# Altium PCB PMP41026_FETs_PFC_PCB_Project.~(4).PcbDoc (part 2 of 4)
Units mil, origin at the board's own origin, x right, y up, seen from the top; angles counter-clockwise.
Board outline 2440.95 x 1417.32 mil, 6 copper layers (Top Layer, Signal Layer 1, Signal Layer 2, Signal Layer 3, Signal Layer 4, Bottom Layer), stack 69.8 mil thick; 61 components, 66 nets, 254 pads, 775 vias.
Unrouted connection lines stored in the file: 2.

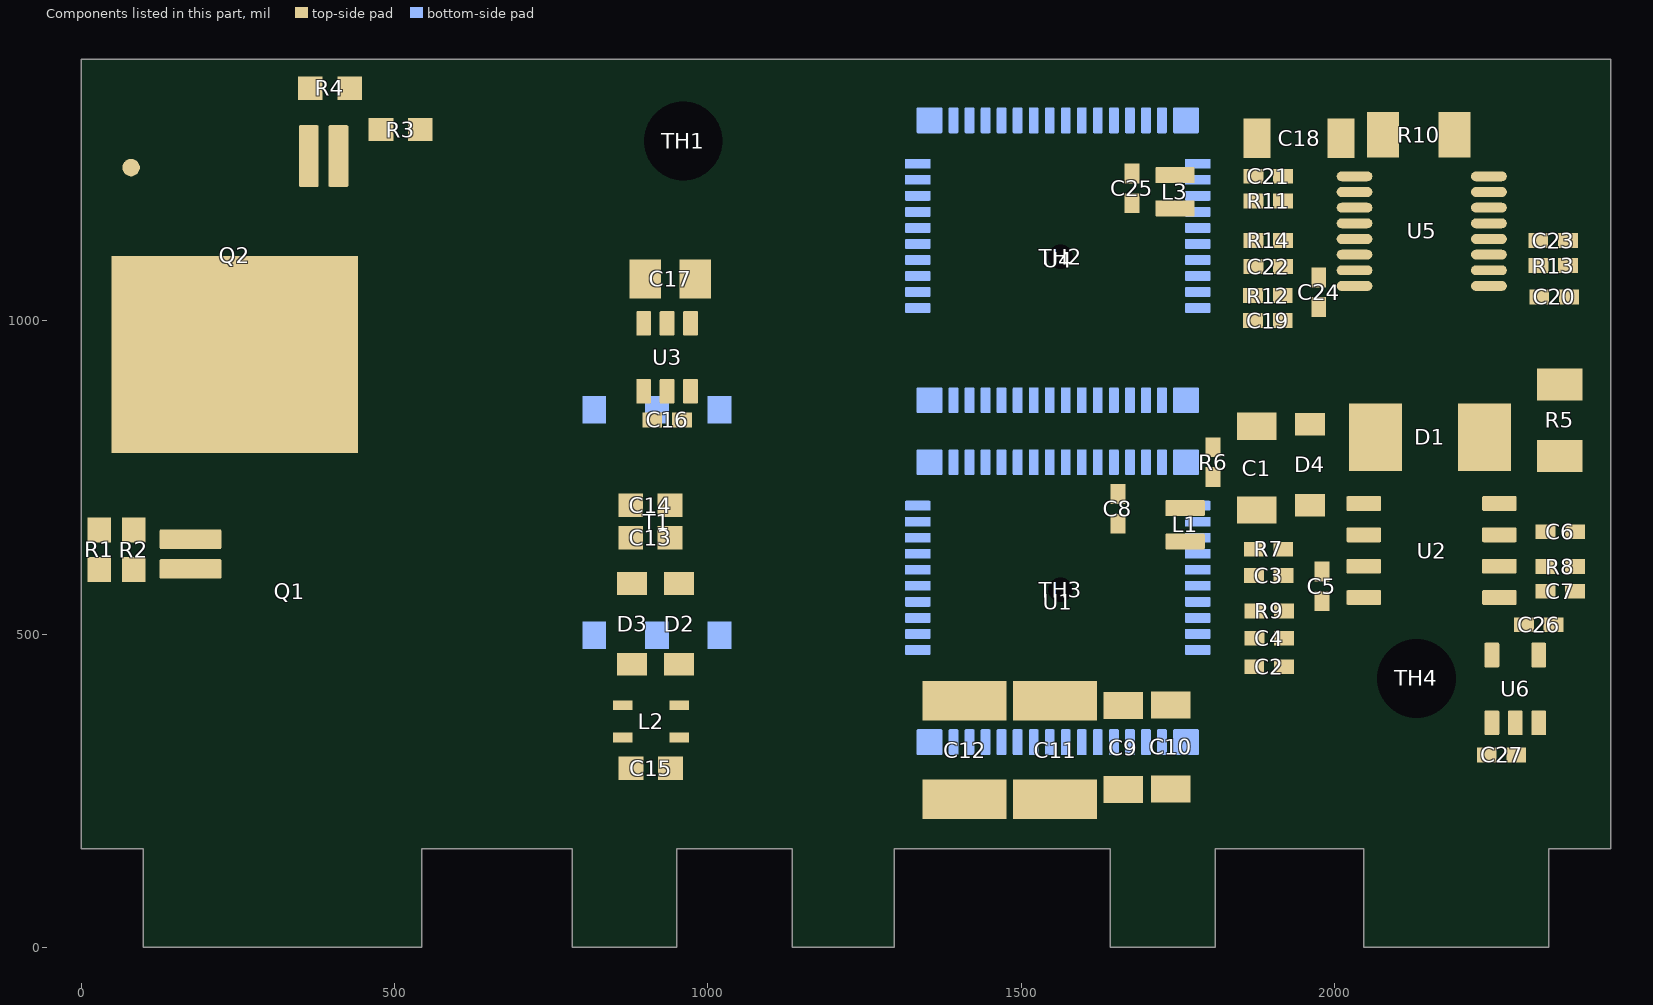
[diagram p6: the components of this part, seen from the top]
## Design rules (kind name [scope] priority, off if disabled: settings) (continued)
PolygonConnect PolygonConnect_38 [All vs IsNamedPolygon('SWNODE') Or  IsNamedPolygon('D403_2') Or  IsNamedPolygon('D403_2') Or  IsNamedPolygon('PGND') Or  IsNamedPolygon('BOTTOM_LAYER_NETC106_2_P030') Or  IsNamedPolygon('C102_1') Or  IsNamedPolygon('SGND') Or  IsNamedPolygon('TOP_LAYER_54V1_P046') Or  IsNamedPolygon('TOP_LAYER_54V2_P048') Or  IsNamedPolygon('TOP_LAYER_54V2_P048') Or  IsNamedPolygon('C108_1') Or  IsNamedPolygon('C108_1') Or  IsNamedPolygon('C108_1') Or  IsNamedPolygon('C108_1') Or  IsNamedPolygon('C108_1') Or  IsNamedPolygon('C108_1') Or  IsNamedPolygon('PGND') Or  IsNamedPolygon('ZCD') Or  IsNamedPolygon('Line') Or  IsNamedPolygon('5Vp') Or  IsNamedPolygon('12Vp') Or  IsNamedPolygon('T200_4') Or  IsNamedPolygon('T200_6') Or  IsNamedPolygon('SWNODE3') Or  IsNamedPolygon('T200_4') Or  IsNamedPolygon('T200_6') Or  IsNamedPolygon('SWNODE4') Or  IsNamedPolygon('VSR') Or  IsNamedPolygon('Iout_SNS') Or  IsNamedPolygon('SIGNAL_LAYER_2_VBB_P094') Or  IsNamedPolygon('Vbulk1') Or  IsNamedPolygon('VBB') Or  IsNamedPolygon('SIGNAL_LAYER_1_VBULK1_P106') Or  IsNamedPolygon('Line') Or  IsNamedPolygon('Line') Or  IsNamedPolygon('Line') Or  IsNamedPolygon('D404_2') Or  IsNamedPolygon('VBB') Or  IsNamedPolygon('D400_2') Or  IsNamedPolygon('SGND') Or  IsNamedPolygon('PGND') Or  IsNamedPolygon('TOP_LAYER_12VS_P126') Or  IsNamedPolygon('BOTTOM_LAYER_54V1_P128') Or  IsNamedPolygon('LEG3_HS_DRV') Or  IsNamedPolygon('LEG4_LS_DRV') Or  IsNamedPolygon('LEG4_HS_DRV') Or  IsNamedPolygon('SWNODE4') Or  IsNamedPolygon('SWNODE3') Or  IsNamedPolygon('T200_6') Or  IsNamedPolygon('T200_4') Or  IsNamedPolygon('VBB') Or  IsNamedPolygon('5Vs') Or  IsNamedPolygon('SGND') Or  IsNamedPolygon('Iout_SNS') Or  IsNamedPolygon('SGND') Or  IsNamedPolygon('SWNODE3') Or  IsNamedPolygon('SWNODE3') Or  IsNamedPolygon('SWNODE3') Or  IsNamedPolygon('SWNODE3') Or  IsNamedPolygon('SGND') Or  IsNamedPolygon('SGND') Or  IsNamedPolygon('SGND') Or  IsNamedPolygon('SWNODE4') Or  IsNamedPolygon('SWNODE4') Or  IsNamedPolygon('SWNODE4') Or  IsNamedPolygon('VSR') Or  IsNamedPolygon('SWNODE3') Or  IsNamedPolygon('SGND') Or  IsNamedPolygon('SGND') Or  IsNamedPolygon('SGND') Or  IsNamedPolygon('SGND') Or  IsNamedPolygon('SGND') Or  IsNamedPolygon('SGND') Or  IsNamedPolygon('BOTTOM_LAYER_54V1_P128') Or  IsNamedPolygon('SGND') Or  IsNamedPolygon('VSR') Or  IsNamedPolygon('C102_1') Or  IsNamedPolygon('C102_1') Or  IsNamedPolygon('C102_1') Or  IsNamedPolygon('C102_1') Or  IsNamedPolygon('C102_1') Or  IsNamedPolygon('ZCD') Or  IsNamedPolygon('PGND') Or  IsNamedPolygon('PGND') Or  IsNamedPolygon('Vbulk1') Or  IsNamedPolygon('VBB') Or  IsNamedPolygon('Vbulk1') Or  IsNamedPolygon('Vbulk1') Or  IsNamedPolygon('ZCD') Or  IsNamedPolygon('Neutral') Or  IsNamedPolygon('Neutral')] p22: connectstyle=Direct reliefconductorwidth=10 reliefentries=4 polygonreliefangle="90 Angle" airgapwidth=10
PolygonConnect PolygonConnect_37 [All vs IsNamedPolygon('SGND') Or  IsNamedPolygon('SWNODE4') Or  IsNamedPolygon('5Vp') Or  IsNamedPolygon('SWNODE4') Or  IsNamedPolygon('VBB') Or  IsNamedPolygon('Line') Or  IsNamedPolygon('SGND') Or  IsNamedPolygon('SIGNAL_LAYER_2_C102_1_P032') Or  IsNamedPolygon('TOP_LAYER_54V2_P048') Or  IsNamedPolygon('ZCD') Or  IsNamedPolygon('PGND') Or  IsNamedPolygon('SIGNAL_LAYER_2_VBB_P094') Or  IsNamedPolygon('Line') Or  IsNamedPolygon('Line') Or  IsNamedPolygon('D404_2') Or  IsNamedPolygon('PGND') Or  IsNamedPolygon('SIGNAL_LAYER_1_ZCD_P108') Or  IsNamedPolygon('SWNODE3') Or  IsNamedPolygon('SIGNAL_LAYER_4_C102_1_P038') Or  IsNamedPolygon('SWNODE3') Or  IsNamedPolygon('LEG4_HS_DRV') Or  IsNamedPolygon('SWNODE4') Or  IsNamedPolygon('5Vs') Or  IsNamedPolygon('VBB') Or  IsNamedPolygon('TOP_LAYER_54V2_P048') Or  IsNamedPolygon('C102_1') Or  IsNamedPolygon('LEG4_LS_DRV') Or  IsNamedPolygon('T200_4') Or  IsNamedPolygon('SWNODE3') Or  IsNamedPolygon('Line') Or  IsNamedPolygon('SGND') Or  IsNamedPolygon('SGND') Or  IsNamedPolygon('SWNODE4') Or  IsNamedPolygon('12Vp') Or  IsNamedPolygon('BOTTOM_LAYER_NETC106_2_P030') Or  IsNamedPolygon('T200_4') Or  IsNamedPolygon('Vbulk1') Or  IsNamedPolygon('C108_1') Or  IsNamedPolygon('BOTTOM_LAYER_54V1_P128') Or  IsNamedPolygon('BOTTOM_LAYER_54V1_P128') Or  IsNamedPolygon('SWNODE') Or  IsNamedPolygon('Iout_SNS') Or  IsNamedPolygon('VSR') Or  IsNamedPolygon('D400_2') Or  IsNamedPolygon('D403_2') Or  IsNamedPolygon('SWNODE3') Or  IsNamedPolygon('T200_6') Or  IsNamedPolygon('SWNODE3') Or  IsNamedPolygon('C108_1') Or  IsNamedPolygon('PGND') Or  IsNamedPolygon('BOTTOM_LAYER_VBULK1_P096') Or  IsNamedPolygon('BOTTOM_LAYER_54V1_P128') Or  IsNamedPolygon('TOP_LAYER_12VS_P126') Or  IsNamedPolygon('SIGNAL_LAYER_1_VBULK1_P106') Or  IsNamedPolygon('T200_4') Or  IsNamedPolygon('SGND') Or  IsNamedPolygon('C108_1') Or  IsNamedPolygon('SWNODE3') Or  IsNamedPolygon('T200_6') Or  IsNamedPolygon('T200_6') Or  IsNamedPolygon('T200_6') Or  IsNamedPolygon('SGND') Or  IsNamedPolygon('C108_1') Or  IsNamedPolygon('SGND') Or  IsNamedPolygon('VBB') Or  IsNamedPolygon('T200_4') Or  IsNamedPolygon('LEG3_HS_DRV') Or  IsNamedPolygon('C108_1') Or  IsNamedPolygon('D403_2') Or  IsNamedPolygon('Iout_SNS') Or  IsNamedPolygon('C108_1') Or  IsNamedPolygon('SWNODE4')] p23: connectstyle=Direct reliefconductorwidth=10 reliefentries=4 polygonreliefangle="90 Angle" airgapwidth=10
PolygonConnect PolygonConnect_36 [All vs IsNamedPolygon('PGND') Or  IsNamedPolygon('BOTTOM_LAYER_54V1_P128') Or  IsNamedPolygon('SGND') Or  IsNamedPolygon('LEG4_LS_DRV') Or  IsNamedPolygon('TOP_LAYER_12VS_P126') Or  IsNamedPolygon('LEG4_HS_DRV') Or  IsNamedPolygon('LEG3_HS_DRV') Or  IsNamedPolygon('SGND') Or  IsNamedPolygon('C108_1') Or  IsNamedPolygon('12Vp') Or  IsNamedPolygon('D403_2') Or  IsNamedPolygon('SIGNAL_LAYER_1_ZCD_P108') Or  IsNamedPolygon('C108_1') Or  IsNamedPolygon('BOTTOM_LAYER_VBULK1_P096') Or  IsNamedPolygon('SWNODE') Or  IsNamedPolygon('T200_4') Or  IsNamedPolygon('D400_2') Or  IsNamedPolygon('C102_1') Or  IsNamedPolygon('Line') Or  IsNamedPolygon('VBB') Or  IsNamedPolygon('Line') Or  IsNamedPolygon('TOP_LAYER_54V2_P048') Or  IsNamedPolygon('BOTTOM_LAYER_NETC106_2_P030') Or  IsNamedPolygon('SIGNAL_LAYER_1_VBULK1_P106') Or  IsNamedPolygon('Line') Or  IsNamedPolygon('5Vp') Or  IsNamedPolygon('BOTTOM_LAYER_54V1_P128') Or  IsNamedPolygon('D404_2') Or  IsNamedPolygon('C108_1') Or  IsNamedPolygon('VSR') Or  IsNamedPolygon('T200_6') Or  IsNamedPolygon('VBB') Or  IsNamedPolygon('C108_1') Or  IsNamedPolygon('SIGNAL_LAYER_2_C102_1_P032') Or  IsNamedPolygon('SGND') Or  IsNamedPolygon('PGND') Or  IsNamedPolygon('SIGNAL_LAYER_4_C102_1_P038') Or  IsNamedPolygon('Vbulk1') Or  IsNamedPolygon('TOP_LAYER_54V2_P048') Or  IsNamedPolygon('Iout_SNS') Or  IsNamedPolygon('PGND') Or  IsNamedPolygon('T200_4') Or  IsNamedPolygon('ZCD') Or  IsNamedPolygon('Line') Or  IsNamedPolygon('C108_1') Or  IsNamedPolygon('D403_2') Or  IsNamedPolygon('SIGNAL_LAYER_2_VBB_P094') Or  IsNamedPolygon('SGND') Or  IsNamedPolygon('C108_1') Or  IsNamedPolygon('SIGNAL_LAYER_1_IOUT_SNS_P044') Or  IsNamedPolygon('BOTTOM_LAYER_54V1_P128') Or  IsNamedPolygon('T200_6')] p24: connectstyle=Direct reliefconductorwidth=10 reliefentries=4 polygonreliefangle="90 Angle" airgapwidth=10
PolygonConnect PolygonConnect_35 [All vs IsNamedPolygon('SWNODE') Or  IsNamedPolygon('D403_2') Or  IsNamedPolygon('D403_2') Or  IsNamedPolygon('PGND') Or  IsNamedPolygon('BOTTOM_LAYER_NETC106_2_P030') Or  IsNamedPolygon('SIGNAL_LAYER_2_C102_1_P032') Or  IsNamedPolygon('C102_1') Or  IsNamedPolygon('SIGNAL_LAYER_4_C102_1_P038') Or  IsNamedPolygon('SGND') Or  IsNamedPolygon('SIGNAL_LAYER_1_IOUT_SNS_P044') Or  IsNamedPolygon('BOTTOM_LAYER_54V1_P128') Or  IsNamedPolygon('TOP_LAYER_54V2_P048') Or  IsNamedPolygon('BOTTOM_LAYER_54V1_P128') Or  IsNamedPolygon('TOP_LAYER_54V2_P048') Or  IsNamedPolygon('C108_1') Or  IsNamedPolygon('C108_1') Or  IsNamedPolygon('C108_1') Or  IsNamedPolygon('C108_1') Or  IsNamedPolygon('C108_1') Or  IsNamedPolygon('C108_1') Or  IsNamedPolygon('PGND') Or  IsNamedPolygon('ZCD') Or  IsNamedPolygon('Line') Or  IsNamedPolygon('5Vp') Or  IsNamedPolygon('12Vp') Or  IsNamedPolygon('T200_4') Or  IsNamedPolygon('T200_6') Or  IsNamedPolygon('SGND') Or  IsNamedPolygon('T200_4') Or  IsNamedPolygon('T200_6') Or  IsNamedPolygon('SGND') Or  IsNamedPolygon('VSR') Or  IsNamedPolygon('Iout_SNS') Or  IsNamedPolygon('SIGNAL_LAYER_2_VBB_P094') Or  IsNamedPolygon('BOTTOM_LAYER_VBULK1_P096') Or  IsNamedPolygon('Vbulk1') Or  IsNamedPolygon('VBB') Or  IsNamedPolygon('SIGNAL_LAYER_1_VBULK1_P106') Or  IsNamedPolygon('SIGNAL_LAYER_1_ZCD_P108') Or  IsNamedPolygon('Line') Or  IsNamedPolygon('Line') Or  IsNamedPolygon('Line') Or  IsNamedPolygon('D404_2') Or  IsNamedPolygon('VBB') Or  IsNamedPolygon('D400_2') Or  IsNamedPolygon('SGND') Or  IsNamedPolygon('PGND') Or  IsNamedPolygon('TOP_LAYER_12VS_P126') Or  IsNamedPolygon('BOTTOM_LAYER_54V1_P128') Or  IsNamedPolygon('LEG3_HS_DRV')] p25: connectstyle=Direct reliefconductorwidth=10 reliefentries=4 polygonreliefangle="90 Angle" airgapwidth=10
PolygonConnect PolygonConnect_34 [All vs IsNamedPolygon('SWNODE') Or  IsNamedPolygon('D403_2') Or  IsNamedPolygon('D403_2') Or  IsNamedPolygon('PGND') Or  IsNamedPolygon('BOTTOM_LAYER_NETC106_2_P030') Or  IsNamedPolygon('SIGNAL_LAYER_2_C102_1_P032') Or  IsNamedPolygon('C102_1') Or  IsNamedPolygon('SIGNAL_LAYER_4_C102_1_P038') Or  IsNamedPolygon('SGND') Or  IsNamedPolygon('SIGNAL_LAYER_1_IOUT_SNS_P044') Or  IsNamedPolygon('BOTTOM_LAYER_54V1_P128') Or  IsNamedPolygon('TOP_LAYER_54V2_P048') Or  IsNamedPolygon('BOTTOM_LAYER_54V1_P128') Or  IsNamedPolygon('TOP_LAYER_54V2_P048') Or  IsNamedPolygon('C108_1') Or  IsNamedPolygon('C108_1') Or  IsNamedPolygon('C108_1') Or  IsNamedPolygon('C108_1') Or  IsNamedPolygon('C108_1') Or  IsNamedPolygon('C108_1') Or  IsNamedPolygon('PGND') Or  IsNamedPolygon('ZCD') Or  IsNamedPolygon('Line') Or  IsNamedPolygon('5Vp') Or  IsNamedPolygon('12Vp') Or  IsNamedPolygon('T200_4') Or  IsNamedPolygon('T200_6') Or  IsNamedPolygon('SGND') Or  IsNamedPolygon('T200_4') Or  IsNamedPolygon('T200_6') Or  IsNamedPolygon('SGND') Or  IsNamedPolygon('VSR') Or  IsNamedPolygon('Iout_SNS') Or  IsNamedPolygon('SIGNAL_LAYER_2_VBB_P094') Or  IsNamedPolygon('BOTTOM_LAYER_VBULK1_P096') Or  IsNamedPolygon('Vbulk1') Or  IsNamedPolygon('VBB') Or  IsNamedPolygon('SIGNAL_LAYER_1_VBULK1_P106') Or  IsNamedPolygon('SIGNAL_LAYER_1_ZCD_P108') Or  IsNamedPolygon('Line') Or  IsNamedPolygon('Line') Or  IsNamedPolygon('Line') Or  IsNamedPolygon('D404_2') Or  IsNamedPolygon('VBB') Or  IsNamedPolygon('D400_2') Or  IsNamedPolygon('SGND')] p26: connectstyle=Direct reliefconductorwidth=10 reliefentries=4 polygonreliefangle="90 Angle" airgapwidth=10
PolygonConnect PolygonConnect_33 [All vs IsNamedPolygon('SIGNAL_LAYER_1_VBULK1_P106')] p27: connectstyle=Direct reliefconductorwidth=10 reliefentries=4 polygonreliefangle="90 Angle" airgapwidth=10
PolygonConnect PolygonConnect_32 [All vs IsNamedPolygon('SIGNAL_LAYER_1_VBULK1_P106')] p28: connectstyle=Direct reliefconductorwidth=10 reliefentries=4 polygonreliefangle="90 Angle" airgapwidth=10
PolygonConnect PolygonConnect_31 [All vs IsNamedPolygon('SIGNAL_LAYER_1_VBULK1_P106')] p29: connectstyle=Direct reliefconductorwidth=10 reliefentries=4 polygonreliefangle="90 Angle" airgapwidth=10
PolygonConnect PolygonConnect_30 [All vs IsNamedPolygon('VBB')] p30: connectstyle=Direct reliefconductorwidth=10 reliefentries=4 polygonreliefangle="90 Angle" airgapwidth=10
PolygonConnect PolygonConnect_29 [All vs IsNamedPolygon('SGND')] p31: connectstyle=Direct reliefconductorwidth=10 reliefentries=4 polygonreliefangle="90 Angle" airgapwidth=10
PolygonConnect PolygonConnect_28 [All vs IsNamedPolygon('Vbulk1')] p32: connectstyle=Direct reliefconductorwidth=10 reliefentries=4 polygonreliefangle="90 Angle" airgapwidth=10
PolygonConnect PolygonConnect_27 [All vs IsNamedPolygon('BOTTOM_LAYER_VBULK1_P096')] p33: connectstyle=Direct reliefconductorwidth=10 reliefentries=4 polygonreliefangle="90 Angle" airgapwidth=10
PolygonConnect PolygonConnect_26 [All vs IsNamedPolygon('SIGNAL_LAYER_2_VBB_P094')] p34: connectstyle=Direct reliefconductorwidth=10 reliefentries=4 polygonreliefangle="90 Angle" airgapwidth=10
PolygonConnect PolygonConnect_25 [All vs IsNamedPolygon('C108_1')] p35: connectstyle=Direct reliefconductorwidth=10 reliefentries=4 polygonreliefangle="90 Angle" airgapwidth=10
PolygonConnect PolygonConnect_24 [All vs IsNamedPolygon('BOTTOM_LAYER_EARTH_P100')] p36: connectstyle=Direct reliefconductorwidth=10 reliefentries=4 polygonreliefangle="90 Angle" airgapwidth=10
PolygonConnect PolygonConnect_23 [All vs IsNamedPolygon('BOTTOM_LAYER_54V1_P128')] p37: connectstyle=Direct reliefconductorwidth=10 reliefentries=4 polygonreliefangle="90 Angle" airgapwidth=10
PolygonConnect PolygonConnect_22 [All vs IsNamedPolygon('BOTTOM_LAYER_VBULK1_P096')] p38: connectstyle=Direct reliefconductorwidth=10 reliefentries=4 polygonreliefangle="90 Angle" airgapwidth=10
PolygonConnect PolygonConnect_21 [All vs IsNamedPolygon('SIGNAL_LAYER_2_VBB_P094')] p39: connectstyle=Direct reliefconductorwidth=10 reliefentries=4 polygonreliefangle="90 Angle" airgapwidth=10
PolygonConnect PolygonConnect_20 [All vs IsNamedPolygon('Iout_SNS')] p40: connectstyle=Direct reliefconductorwidth=10 reliefentries=4 polygonreliefangle="90 Angle" airgapwidth=10
PolygonConnect PolygonConnect_19 [All vs IsNamedPolygon('C108_1') Or  IsNamedPolygon('BOTTOM_LAYER_NETC106_2_P030') Or  IsNamedPolygon('D403_2') Or  IsNamedPolygon('C102_1') Or  IsNamedPolygon('SWNODE') Or  IsNamedPolygon('D403_2') Or  IsNamedPolygon('SIGNAL_LAYER_4_C102_1_P038') Or  IsNamedPolygon('PGND') Or  IsNamedPolygon('SIGNAL_LAYER_2_C102_1_P032') Or  IsNamedPolygon('SIGNAL_LAYER_1_IOUT_SNS_P044') Or  IsNamedPolygon('SGND') Or  IsNamedPolygon('C108_1') Or  IsNamedPolygon('BOTTOM_LAYER_54V1_P128') Or  IsNamedPolygon('C108_1') Or  IsNamedPolygon('C108_1') Or  IsNamedPolygon('TOP_LAYER_54V2_P048') Or  IsNamedPolygon('BOTTOM_LAYER_54V1_P128') Or  IsNamedPolygon('TOP_LAYER_54V2_P048') Or  IsNamedPolygon('C108_1') Or  IsNamedPolygon('C108_1') Or  IsNamedPolygon('12Vp') Or  IsNamedPolygon('5Vp') Or  IsNamedPolygon('Line') Or  IsNamedPolygon('T200_4') Or  IsNamedPolygon('SGND') Or  IsNamedPolygon('VSR') Or  IsNamedPolygon('ZCD') Or  IsNamedPolygon('PGND') Or  IsNamedPolygon('T200_6') Or  IsNamedPolygon('Neutral') Or  IsNamedPolygon('T200_4') Or  IsNamedPolygon('SGND') Or  IsNamedPolygon('T200_6')] p41: connectstyle=Direct reliefconductorwidth=10 reliefentries=4 polygonreliefangle="90 Angle" airgapwidth=10
PolygonConnect PolygonConnect_18 [All vs IsNamedPolygon('SWNODE') Or  IsNamedPolygon('D403_2') Or  IsNamedPolygon('D403_2') Or  IsNamedPolygon('PGND') Or  IsNamedPolygon('BOTTOM_LAYER_NETC106_2_P030') Or  IsNamedPolygon('SIGNAL_LAYER_2_C102_1_P032') Or  IsNamedPolygon('C102_1') Or  IsNamedPolygon('SIGNAL_LAYER_4_C102_1_P038') Or  IsNamedPolygon('SGND') Or  IsNamedPolygon('SIGNAL_LAYER_1_IOUT_SNS_P044') Or  IsNamedPolygon('BOTTOM_LAYER_54V1_P128') Or  IsNamedPolygon('TOP_LAYER_54V2_P048') Or  IsNamedPolygon('BOTTOM_LAYER_54V1_P128') Or  IsNamedPolygon('TOP_LAYER_54V2_P048') Or  IsNamedPolygon('C108_1') Or  IsNamedPolygon('C108_1') Or  IsNamedPolygon('C108_1') Or  IsNamedPolygon('C108_1') Or  IsNamedPolygon('C108_1') Or  IsNamedPolygon('C108_1') Or  IsNamedPolygon('Neutral') Or  IsNamedPolygon('PGND') Or  IsNamedPolygon('ZCD') Or  IsNamedPolygon('Line') Or  IsNamedPolygon('5Vp') Or  IsNamedPolygon('12Vp') Or  IsNamedPolygon('T200_4') Or  IsNamedPolygon('T200_6') Or  IsNamedPolygon('SGND') Or  IsNamedPolygon('T200_4') Or  IsNamedPolygon('T200_6') Or  IsNamedPolygon('SGND')] p42: connectstyle=Direct reliefconductorwidth=10 reliefentries=4 polygonreliefangle="90 Angle" airgapwidth=10
PolygonConnect PolygonConnect_17 [All vs IsNamedPolygon('12Vp') Or  IsNamedPolygon('T200_4') Or  IsNamedPolygon('T200_6') Or  IsNamedPolygon('SGND') Or  IsNamedPolygon('TOP_LAYER_54V2_P048') Or  IsNamedPolygon('SIGNAL_LAYER_1_IOUT_SNS_P044') Or  IsNamedPolygon('BOTTOM_LAYER_54V1_P128') Or  IsNamedPolygon('SGND') Or  IsNamedPolygon('C102_1') Or  IsNamedPolygon('SIGNAL_LAYER_4_C102_1_P038') Or  IsNamedPolygon('Neutral') Or  IsNamedPolygon('C108_1') Or  IsNamedPolygon('C108_1') Or  IsNamedPolygon('C108_1') Or  IsNamedPolygon('BOTTOM_LAYER_54V1_P128') Or  IsNamedPolygon('TOP_LAYER_54V2_P048') Or  IsNamedPolygon('SIGNAL_LAYER_2_C102_1_P032') Or  IsNamedPolygon('SWNODE') Or  IsNamedPolygon('C108_1') Or  IsNamedPolygon('C108_1') Or  IsNamedPolygon('C108_1') Or  IsNamedPolygon('D403_2') Or  IsNamedPolygon('BOTTOM_LAYER_NETC106_2_P030') Or  IsNamedPolygon('PGND') Or  IsNamedPolygon('D403_2') Or  IsNamedPolygon('5Vp') Or  IsNamedPolygon('PGND') Or  IsNamedPolygon('ZCD') Or  IsNamedPolygon('Line')] p43: connectstyle=Direct reliefconductorwidth=10 reliefentries=4 polygonreliefangle="90 Angle" airgapwidth=10
PolygonConnect PolygonConnect_16 [All vs IsNamedPolygon('D403_2') Or  IsNamedPolygon('C102_1') Or  IsNamedPolygon('C108_1') Or  IsNamedPolygon('SWNODE') Or  IsNamedPolygon('BOTTOM_LAYER_54V1_P128') Or  IsNamedPolygon('SGND') Or  IsNamedPolygon('Line') Or  IsNamedPolygon('ZCD') Or  IsNamedPolygon('SIGNAL_LAYER_1_IOUT_SNS_P044') Or  IsNamedPolygon('Neutral') Or  IsNamedPolygon('PGND') Or  IsNamedPolygon('12Vp') Or  IsNamedPolygon('C108_1') Or  IsNamedPolygon('C108_1') Or  IsNamedPolygon('TOP_LAYER_54V2_P048') Or  IsNamedPolygon('C108_1') Or  IsNamedPolygon('TOP_LAYER_54V2_P048') Or  IsNamedPolygon('T200_4') Or  IsNamedPolygon('T200_6') Or  IsNamedPolygon('D403_2') Or  IsNamedPolygon('C108_1') Or  IsNamedPolygon('C108_1') Or  IsNamedPolygon('SIGNAL_LAYER_4_C102_1_P038') Or  IsNamedPolygon('SIGNAL_LAYER_2_C102_1_P032') Or  IsNamedPolygon('PGND') Or  IsNamedPolygon('BOTTOM_LAYER_NETC106_2_P030') Or  IsNamedPolygon('5Vp') Or  IsNamedPolygon('BOTTOM_LAYER_54V1_P128')] p44: connectstyle=Direct reliefconductorwidth=10 reliefentries=4 polygonreliefangle="90 Angle" airgapwidth=10
PolygonConnect PolygonConnect_15 [All vs IsNamedPolygon('SWNODE') Or  IsNamedPolygon('D403_2') Or  IsNamedPolygon('D403_2') Or  IsNamedPolygon('SIGNAL_LAYER_1_PGND_P018') Or  IsNamedPolygon('PGND') Or  IsNamedPolygon('BOTTOM_LAYER_NETC106_2_P030') Or  IsNamedPolygon('SIGNAL_LAYER_2_C102_1_P032') Or  IsNamedPolygon('C102_1') Or  IsNamedPolygon('SIGNAL_LAYER_4_C102_1_P038') Or  IsNamedPolygon('SGND') Or  IsNamedPolygon('SIGNAL_LAYER_1_IOUT_SNS_P044') Or  IsNamedPolygon('BOTTOM_LAYER_54V1_P128') Or  IsNamedPolygon('TOP_LAYER_54V2_P048') Or  IsNamedPolygon('BOTTOM_LAYER_54V1_P128') Or  IsNamedPolygon('TOP_LAYER_54V2_P048') Or  IsNamedPolygon('C108_1') Or  IsNamedPolygon('C108_1') Or  IsNamedPolygon('C108_1') Or  IsNamedPolygon('C108_1') Or  IsNamedPolygon('C108_1') Or  IsNamedPolygon('C108_1') Or  IsNamedPolygon('Neutral') Or  IsNamedPolygon('PGND') Or  IsNamedPolygon('ZCD') Or  IsNamedPolygon('Line') Or  IsNamedPolygon('5Vp') Or  IsNamedPolygon('12Vp')] p45: connectstyle=Direct reliefconductorwidth=10 reliefentries=4 polygonreliefangle="90 Angle" airgapwidth=10
PolygonConnect PolygonConnect_14 [All vs IsNamedPolygon('TOP_LAYER_54V2_P048') Or  IsNamedPolygon('C108_1') Or  IsNamedPolygon('C108_1') Or  IsNamedPolygon('SIGNAL_LAYER_4_C102_1_P038') Or  IsNamedPolygon('C102_1') Or  IsNamedPolygon('SIGNAL_LAYER_2_C102_1_P032') Or  IsNamedPolygon('SIGNAL_LAYER_1_PGND_P018') Or  IsNamedPolygon('SIGNAL_LAYER_1_IOUT_SNS_P044') Or  IsNamedPolygon('SGND') Or  IsNamedPolygon('C108_1') Or  IsNamedPolygon('ZCD') Or  IsNamedPolygon('PGND') Or  IsNamedPolygon('TOP_LAYER_54V2_P048') Or  IsNamedPolygon('BOTTOM_LAYER_NETC106_2_P030') Or  IsNamedPolygon('PGND') Or  IsNamedPolygon('C108_1') Or  IsNamedPolygon('C108_1') Or  IsNamedPolygon('D403_2') Or  IsNamedPolygon('Line') Or  IsNamedPolygon('C108_1') Or  IsNamedPolygon('Neutral') Or  IsNamedPolygon('SWNODE') Or  IsNamedPolygon('D403_2') Or  IsNamedPolygon('BOTTOM_LAYER_54V1_P128') Or  IsNamedPolygon('BOTTOM_LAYER_54V1_P128')] p46: connectstyle=Direct reliefconductorwidth=10 reliefentries=4 polygonreliefangle="90 Angle" airgapwidth=10
PolygonConnect PolygonConnect_13 [All vs IsNamedPolygon('PGND') Or  IsNamedPolygon('D403_2') Or  IsNamedPolygon('SIGNAL_LAYER_1_PGND_P018') Or  IsNamedPolygon('D403_2') Or  IsNamedPolygon('SWNODE') Or  IsNamedPolygon('SGND') Or  IsNamedPolygon('BOTTOM_LAYER_54V1_P128') Or  IsNamedPolygon('C108_1') Or  IsNamedPolygon('SIGNAL_LAYER_4_C102_1_P038') Or  IsNamedPolygon('C108_1') Or  IsNamedPolygon('TOP_LAYER_54V2_P048') Or  IsNamedPolygon('TOP_LAYER_54V2_P048') Or  IsNamedPolygon('C108_1') Or  IsNamedPolygon('C108_1') Or  IsNamedPolygon('C108_1') Or  IsNamedPolygon('BOTTOM_LAYER_NETC106_2_P030') Or  IsNamedPolygon('SIGNAL_LAYER_1_IOUT_SNS_P044') Or  IsNamedPolygon('C108_1') Or  IsNamedPolygon('C102_1') Or  IsNamedPolygon('SIGNAL_LAYER_2_C102_1_P032') Or  IsNamedPolygon('BOTTOM_LAYER_54V1_P128')] p47: connectstyle=Direct reliefconductorwidth=10 reliefentries=4 polygonreliefangle="90 Angle" airgapwidth=10
PolygonConnect PolygonConnect_12 [All vs IsNamedPolygon('TOP_LAYER_54V2_P048')] p48: connectstyle=Direct reliefconductorwidth=10 reliefentries=4 polygonreliefangle="90 Angle" airgapwidth=10
PolygonConnect PolygonConnect_11 [All vs IsNamedPolygon('BOTTOM_LAYER_54V1_P128')] p49: connectstyle=Direct reliefconductorwidth=10 reliefentries=4 polygonreliefangle="90 Angle" airgapwidth=10
PolygonConnect PolygonConnect_10 [All vs IsNamedPolygon('SIGNAL_LAYER_1_IOUT_SNS_P044')] p50: thpad.connectstyle=Direct thpad.reliefconductorwidth=10 thpad.reliefentries=4 thpad.polygonreliefangle="90 Angle" thpad.airgapwidth=10 smdpad.connectstyle=Relief smdpad.reliefconductorwidth=10 smdpad.reliefentries=4 smdpad.polygonreliefangle="90 Angle" smdpad.airgapwidth=10 via.connectstyle=Direct via.reliefconductorwidth=10 via.reliefentries=4 via.polygonreliefangle="90 Angle" via.airgapwidth=10
PolygonConnect PolygonConnect_9 [All vs IsNamedPolygon('SGND')] p51: thpad.connectstyle=Direct thpad.reliefconductorwidth=10 thpad.reliefentries=4 thpad.polygonreliefangle="90 Angle" thpad.airgapwidth=10 smdpad.connectstyle=Relief smdpad.reliefconductorwidth=10 smdpad.reliefentries=4 smdpad.polygonreliefangle="90 Angle" smdpad.airgapwidth=10 via.connectstyle=Direct via.reliefconductorwidth=10 via.reliefentries=4 via.polygonreliefangle="90 Angle" via.airgapwidth=10
PolygonConnect PolygonConnect_8 [All vs IsNamedPolygon('SGND')] p52: thpad.connectstyle=Direct thpad.reliefconductorwidth=10 thpad.reliefentries=4 thpad.polygonreliefangle="90 Angle" thpad.airgapwidth=10 smdpad.connectstyle=Relief smdpad.reliefconductorwidth=10 smdpad.reliefentries=4 smdpad.polygonreliefangle="90 Angle" smdpad.airgapwidth=10 via.connectstyle=Direct via.reliefconductorwidth=10 via.reliefentries=4 via.polygonreliefangle="90 Angle" via.airgapwidth=10
PolygonConnect PolygonConnect_7 [All vs IsNamedPolygon('SGND')] p53: thpad.connectstyle=Relief thpad.reliefconductorwidth=0 thpad.reliefentries=4 thpad.polygonreliefangle="90 Angle" thpad.airgapwidth=0 smdpad.connectstyle=Relief smdpad.reliefconductorwidth=10 smdpad.reliefentries=4 smdpad.polygonreliefangle="90 Angle" smdpad.airgapwidth=10 via.connectstyle=Relief via.reliefconductorwidth=10 via.reliefentries=4 via.polygonreliefangle="90 Angle" via.airgapwidth=10
PolygonConnect PolygonConnect_6 [All vs IsNamedPolygon('SGND')] p54: thpad.connectstyle=Direct thpad.reliefconductorwidth=10 thpad.reliefentries=4 thpad.polygonreliefangle="90 Angle" thpad.airgapwidth=10 smdpad.connectstyle=Relief smdpad.reliefconductorwidth=10 smdpad.reliefentries=4 smdpad.polygonreliefangle="90 Angle" smdpad.airgapwidth=10 via.connectstyle=Relief via.reliefconductorwidth=10 via.reliefentries=4 via.polygonreliefangle="90 Angle" via.airgapwidth=10
PolygonConnect PolygonConnect_5 [All vs IsNamedPolygon('SGND')] p55: thpad.connectstyle=Direct thpad.reliefconductorwidth=10 thpad.reliefentries=4 thpad.polygonreliefangle="90 Angle" thpad.airgapwidth=10 smdpad.connectstyle=Relief smdpad.reliefconductorwidth=10 smdpad.reliefentries=4 smdpad.polygonreliefangle="90 Angle" smdpad.airgapwidth=10 via.connectstyle=Relief via.reliefconductorwidth=10 via.reliefentries=4 via.polygonreliefangle="90 Angle" via.airgapwidth=10
PolygonConnect PolygonConnect_4 [All vs IsNamedPolygon('SIGNAL_LAYER_1_PGND_P018') Or  IsNamedPolygon('SWNODE') Or  IsNamedPolygon('D403_2') Or  IsNamedPolygon('SIGNAL_LAYER_4_C102_1_P038') Or  IsNamedPolygon('D403_2') Or  IsNamedPolygon('BOTTOM_LAYER_NETC106_2_P030') Or  IsNamedPolygon('C102_1') Or  IsNamedPolygon('PGND') Or  IsNamedPolygon('SIGNAL_LAYER_2_C102_1_P032')] p56: connectstyle=Direct reliefconductorwidth=10 reliefentries=4 polygonreliefangle="90 Angle" airgapwidth=10
PolygonConnect PolygonConnect_3 [All vs IsNamedPolygon('SWNODE') Or  IsNamedPolygon('D403_2') Or  IsNamedPolygon('Neutral') Or  IsNamedPolygon('C106_2') Or  IsNamedPolygon('D403_2') Or  IsNamedPolygon('Neutral') Or  IsNamedPolygon('Neutral')] p57: connectstyle=Direct reliefconductorwidth=10 reliefentries=4 polygonreliefangle="90 Angle" airgapwidth=10
PolygonConnect PolygonConnect_2 [All vs IsNamedPolygon('Neutral') Or  IsNamedPolygon('Neutral') Or  IsNamedPolygon('C106_2') Or  IsNamedPolygon('SWNODE') Or  IsNamedPolygon('Neutral')] p58: connectstyle=Direct reliefconductorwidth=10 reliefentries=4 polygonreliefangle="90 Angle" airgapwidth=10
PolygonConnect PolygonConnect_1 [All vs IsNamedPolygon('Neutral') Or  IsNamedPolygon('Neutral')] p59: connectstyle=Direct reliefconductorwidth=10 reliefentries=4 polygonreliefangle="90 Angle" airgapwidth=10
PolygonConnect [All] p60: connectstyle=Direct reliefconductorwidth=10 reliefentries=4 polygonreliefangle="90 Angle" airgapwidth=10
RoutingVias ThermalPadVias [IsVia and InAnyComponent] p1: holewidth=7.87 width=19.68 viastyle="Through Hole" minholewidth=7.87 minwidth=8 maxholewidth=12.99 maxwidth=23.62
RoutingVias [All] p2: holewidth=10 width=34 viastyle="Through Hole" minholewidth=7.87 minwidth=8 maxholewidth=40 maxwidth=65
SilkToBoardRegionClearance [Not ((IsComment or IsDesignator) And (Hide <> 'False')) and not InRegion(1000,500,4000,800)] p1:
SilkToSilkClearance SilkToSilkClearance_Pb-FreeLogo [(HasFootprint('Pb-Free_Overlay_Medium') OR HasFootprint('Pb-Free_Overlay_Small')) vs (HasFootprint('Pb-Free_Overlay_Medium') OR HasFootprint('Pb-Free_Overlay_Small'))] p1: silktosilkclearance=0
SilkToSilkClearance [All] p2: silktosilkclearance=4
SilkToSolderMaskClearance SilkToComponentPadClearance [(IsPad or IsFill or IsRegion) and InAnycomponent] p1: minsilkscreentomaskgap=2 clearancetoexposedcopper=TRUE
SilkToSolderMaskClearance "Silk to Solder Mask Opening" [All] p2: minsilkscreentomaskgap=2 clearancetoexposedcopper=FALSE
SolderMaskExpansion [All] p1: expansion=1.97
Width [All] p1: maxlimit=100 minlimit=6 preferedwidth=10 checkconnectedcopper=TRUE
13 further rules are at their usual default settings.

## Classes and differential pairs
component class PMP41026_FETs_Si_PFC_PCB_Project: !PCB2 Q1 Q2 R1 R2 R3 R4
net class AC: +BRDG_N NetQ1_1 Neutral
net class INGND: 3V3 5V 12V AGND Bot_FET_FAULT NetC6_1 NetC23_1 NetT1_4 NetT1_6 PFC_Temp3 TTP_HSDRV1 TTP_LSDRV1 U3NC11
net class PGND: 5V_L NCU627 NCU643 NCU647 NCU652 NetC18_1 NetC21_2 NetC22_2 NetC25_1 NetD1_2 NetL3_2 NetR11_1 NetU4_46 NetU4_49 PGND U3NC6 U6OC
net class Screw: NC1 NC3
net class HV: NCU51 NCU516 Vbulk1
net class VSWNET: 5V_H ISO_12V_H NCT1 NCU61 NCU527 NCU543 NCU547 NCU552 NCU616 NetC1_1 NetC3_2 NetC4_2 NetC8_1 NetC13_1 NetC13_2 NetC14_2 NetD2_2 NetL1_2 NetR7_2 SW U2NC7 U5FAULT U5OC U5TEMP

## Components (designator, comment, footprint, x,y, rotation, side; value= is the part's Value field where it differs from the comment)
C1 "C3216X7R1E106M160AE" 1206_190 1876.29,764.89 r90 top value=10uF
C2 "CL05B224KO5NNNC" 0402 1896,447.79 r180 top value=0.22uF
C3 "04025A101FAT2A" 0402 1895.28,593.42 r180 top value=100pF
C4 "04025A101FAT2A" 0402 1896.09,493.26 r180 top value=100pF
C5 "C1005X7R1H104K050BB" 0402 1980.28,576.22 r90 top value=0.1uF
C6 "04025A101FAT2A" 0402 2360.65,663.42 r0 top value=100pF
C7 "C1005X5R1E105K050BC" 0402 2360.65,568.42 r0 top value=1uF
C8 "GRT155R61E225KE13D" 0402 1654.58,699.86 r270 top value=2.2uF
C9 "C1206C223KDRACTU" 1206_190 1662.91,318.79 r90 top value=0.022uF
C10 "C1206C223KDRACTU" 1206_190 1738.96,319.77 r90 top value=0.022uF
C11 "C1812W104KDRACTU" 1812_254 1554.15,314.77 r90 top value=0.1uF
C12 "C1812W104KDRACTU" 1812_254 1409.74,314.77 r90 top value=0.1uF
C13 "C1608X5R1V475K080AC" 0603 908.14,653.86 r180 top value=4.7uF
C14 "C1608X5R1V475K080AC" 0603 908.14,705.47 r0 top value=4.7uF
C15 "C1608X5R1V475K080AC" 0603 908.7,285.76 r0 top value=4.7uF
C16 "C1005X7R1H104K050BB" 0402 934.87,841.88 r0 top value=0.1uF
C17 "GCM21BR71C475KA73L" 0805_HV 939.87,1066.88 r180 top value=4.7uF
C18 "C3216X7R1E106M160AE" 1206_190 1943.74,1291.67 r0 top value=10uF
C19 "CL05B224KO5NNNC" 0402 1893.96,1000.44 r180 top value=0.22uF
C20 "C1005X5R1E105K050BC" 0402 2350.9,1038.25 r180 top value=1uF
C21 "04025A101FAT2A" 0402 1894.58,1230.75 r180 top value=100pF
C22 "04025A101FAT2A" 0402 1894.53,1086.59 r180 top value=100pF
C23 "04025A101FAT2A" 0402 2349.27,1128.25 r0 top value=100pF
C24 "C1005X7R1H104K050BB" 0402 1975.25,1045.75 r90 top value=0.1uF
C25 "GRT155R61E225KE13D" 0402 1676.91,1211.52 r270 top value=2.2uF
C26 "GRM155R70J104KA01D" 0402 2326.4,514.86 r0 top value=0.1uF
C27 "GRM155R70J104KA01D" 0402 2266.96,307.03 r0 top value=0.1uF
D1 "GB01SLT06-214" SMB 2152.6,814.39 r0 top value=650V
D2 "MBR0520LT1G" SOD-123 953.91,516.33 r270 top value=20V
D3 "MBR0520LT1G" SOD-123 878.91,516.33 r90 top value=20V
D4 "BZT52C16-7-F" SOD-123 1961.09,770.31 r270 top value=16V
L1 "SDEM20161T-4R7MS" FP-SDEM20161T-4R7MS_SMD2-MFG 1761.71,674.51 r90 top
L2 "ACM2520-601-2P-T002" TDK_ACM2520-2P 909.19,360.76 r180 top
L3 "SDEM20161T-4R7MS" FP-SDEM20161T-4R7MS_SMD2-MFG 1745.67,1206.06 r90 top
Q1 "IPT60R022S7XTMA1" FP-IPT60R080G7XTMA1_HSOF-8-MFG#1 384.69,486.03 r270 top
Q2 "IPT60R022S7XTMA1" FP-IPT60R080G7XTMA1_HSOF-8-MFG#2 244.87,1052.49 r180 top
R1 "CRCW060310R0FKEA" 0603 28.13,634.59 r90 top value=10.0
R2 "CRCW060310K0FKEA" 0603 83.8,634.59 r90 top value=10.0k
R3 "CRCW060310R0FKEA" 0603 509.54,1305.48 r180 top value=10.0
R4 "CRCW060310K0FKEA" 0603 396.53,1371.23 r0 top value=10.0k
R5 "CRCW12061R80JNEA" 1206 2360.16,841.24 r270 top value=1.8
R6 "ERJ-2GE0R00X" 0402 1806.45,774.55 r270 top value=0
R7 "RC0402FR-0749R9L" 0402 1895,635.4 r0 top value=49.9
R8 "RC0402FR-0749R9L" 0402 2360.65,607.89 r180 top value=49.9
R9 "CRCW040220K0FKED" 0402 1896.09,536.92 r180 top value=20.0k
R10 "ERJ-8GEY0R00V" 1206 2135.07,1297.1 r180 top value=0
R11 "RC0402FR-0749R9L" 0402 1894.53,1191.2 r180 top value=49.9
R12 "ERJ-2GE0R00X" 0402 1893.96,1040.44 r0 top value=0
R13 "RC0402FR-0749R9L" 0402 2349.53,1088.25 r180 top value=49.9
R14 "CRCW040220K0FKED" 0402 1894.53,1128.25 r180 top value=20.0k
T1 "760390014" Wurth_760390013 918.7,678.26 r90 bottom value=475uH
TH1 "" TP_H045P075#1 926.23,701.85 r90 top
TH2 "" TP_H045P075#2 1536.71,1056.88 r90 top
TH3 "" TP_H045P075#3 1596.12,651.08 r90 top
TH4 "" TP_H045P075#4 1934.5,296.06 r90 top
U1 "LMG3522R030Q" RQS0052A-MFG 1558.49,550.91 r90 bottom
U2 "ISO7710FQDQ1" D0008B_HV 2155.28,633.42 r180 top
U3 "SN6505BDBVR" DBV0006A_N 934.87,941.88 r90 top
U4 "LMG3522R030Q" RQS0052A-MFG 1558.49,1096.68 r90 bottom
U5 "ISO7731FDBQR" DBQ0016A_N 2139.53,1143.25 r0 top
U6 "TLV74133PDBVR" DBV0005A_N 2288.91,412.45 r90 top

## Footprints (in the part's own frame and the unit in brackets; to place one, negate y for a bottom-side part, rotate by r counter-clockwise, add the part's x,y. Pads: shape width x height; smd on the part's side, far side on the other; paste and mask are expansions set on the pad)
0402 [mm] "0402 from SM-752 data"
  rect 0.8x0.6 smd: 1(-0.6,0) 2(0.6,0)
  silkscreen extent -1.22,-0.52 1.22,0.52, body extent -0.55,-0.3 0.55,0.3, height 0.6
0603 [mm] "0603 from SM-752 data"
  rect 1x0.95 smd: 1(-0.8,0) 2(0.8,0)
  silkscreen extent -1.52,-0.69 1.52,0.69, body extent -0.87,-0.47 0.87,0.47, height 1
0805_HV [mil] "0805 with 30mil clearance between pads"
  rect 50x63 smd: 1(-40,0) 2(40,0)
  silkscreen extent -74,-40 74,40, body extent -43,-29 43,29, height 57
1206 [mm] "1206 from SM-752 data"
  rect 1.3x1.85 smd: 1(-1.45,0) 2(1.45,0)
  silkscreen extent -2.4,-1.21 2.4,1.21, body extent -1.7,-0.9 1.7,0.9, height 1.35
1206_190 [mm] "1206_190"
  rect 1.1x1.6 smd: 1(-1.7,0) 2(1.7,0)
  silkscreen extent -0.9,-1 0.9,1, body extent -1.75,-0.95 1.75,0.95, height 1.9
1812_254 [mm] "SMD, 2-Leads, Body 4.8x3.4mm"
  rect 1.6x3.4 smd: 1(-2,0) 2(2,0)
  silkscreen extent -0.8,-1.7 0.8,1.7, body extent -2.4,-1.7 2.4,1.7, height 2.54
D0008B_HV [mm] "SOIC, 8-Leads, Body 4.9x3.9mm, Pitch 1.27mm, HV / Isolation option"
  rrect17% 1.4x0.6 smd: 1(-2.75,1.905) 2(-2.75,0.635) 3(-2.75,-0.635) 4(-2.75,-1.905) 5(2.75,-1.905) 6(2.75,-0.635) 7(2.75,0.635) 8(2.75,1.905)
  silkscreen extent -3.3,-2.5 0.9,2.5, body extent -3,-2.45 3,2.45, height 1.63
DBQ0016A_N [mm] "SOP, 16-Leads, Body 4.9x3.9mm, Pitch 0.635mm, IPC Medium Density"
  oval 1.45x0.4 smd: 1(-2.725,2.222) 2(-2.725,1.587) 3(-2.725,0.953) 4(-2.725,0.318) 5(-2.725,-0.318) 6(-2.725,-0.953) 7(-2.725,-1.587) 8(-2.725,-2.222) 9(2.725,-2.222) 10(2.725,-1.587) 11(2.725,-0.953) 12(2.725,-0.318) 13(2.725,0.318) 14(2.725,0.953) 15(2.725,1.587) 16(2.725,2.222)
  silkscreen extent -3.35,-2.5 1.1,2.68, body extent -3.01,-2.45 3.01,2.45, height 1.63
DBV0005A_N [mm] "SOT23, 5-Leads, Body 2.9x1.6mm, Pitch 0.95mm, Lead Span 2.8mm, IPC Medium Density"
  rrect17% 1x0.6 smd: 1(-1.375,0.95) 2(-1.375,0) 3(-1.375,-0.95) 4(1.375,-0.95) 5(1.375,0.95)
  silkscreen extent -0.25,-1.55 0.25,1.55, body extent -1.42,-1.46 1.42,1.46, height 0.28
DBV0006A_N [mm] "SOT23, 6-Leads, Body 2.9x1.6mm, Pitch 0.95mm, Lead Span 2.8mm, IPC Medium Density"
  rrect17% 1x0.6 smd: 1(-1.375,0.95) 2(-1.375,0) 3(-1.375,-0.95) 4(1.375,-0.95) 5(1.375,0) 6(1.375,0.95)
  silkscreen extent -1.68,-1.55 0.5,1.55, body extent -1.42,-1.46 1.42,1.46, height 1.12
FP-IPT60R080G7XTMA1_HSOF-8-MFG#1 [mm]
  rrect13% 0.8x2.5 smd paste-1000 mask+0: 1(-4.2,-5.35) 2(-3,-5.35)
  rect 10x8 on Top Solder paste-1000 mask+0: 9(0,2.7)
  Top Layer region: -4.85,-1.3 4.85,-1.3 4.85,2.4 4.35,2.4 4.35,5.2 5.05,5.2 5.05,6.7 -5.05,6.7 -5.05,5.2 -4.35,5.2 -4.35,2.4 -4.85,2.4
  Top Layer region: -2.2,-4.1 4.6,-4.1 4.6,-6.6 3.8,-6.6 3.8,-4.6 3.4,-4.6 3.4,-6.6 2.6,-6.6 2.6,-4.6 2.2,-4.6 2.2,-6.6 1.4,-6.6 1.4,-4.6 1,-4.6 1,-6.6 0.2,-6.6 0.2,-4.6 -0.2,-4.6 -0.2,-6.6 -1,-6.6 -1,-4.6 -1.4,-4.6 -1.4,-6.6 -2.2,-6.6 -2.2,-4.1
  body extent -4.95,-5.79 4.95,5.89, height 2.31
FP-IPT60R080G7XTMA1_HSOF-8-MFG#2 [mm]
  rrect13% 0.8x2.5 smd paste-1000 mask+0: 1(-4.2,-5.35) 2(-3,-5.35)
  round 0.709 smd paste-1000 mask+0: 3-4-5-6-7-8(4.206,-4.881)
  rect 10x8 smd paste-1000 mask+0: 9(0,2.7)
  Top Layer region: -4.85,-1.3 4.85,-1.3 4.85,2.4 4.35,2.4 4.35,5.2 5.05,5.2 5.05,6.7 -5.05,6.7 -5.05,5.2 -4.35,5.2 -4.35,2.4 -4.85,2.4
  Top Layer region: -2.2,-4.1 4.6,-4.1 4.6,-6.6 3.8,-6.6 3.8,-4.6 3.4,-4.6 3.4,-6.6 2.6,-6.6 2.6,-4.6 2.2,-4.6 2.2,-6.6 1.4,-6.6 1.4,-4.6 1,-4.6 1,-6.6 0.2,-6.6 0.2,-4.6 -0.2,-4.6 -0.2,-6.6 -1,-6.6 -1,-4.6 -1.4,-4.6 -1.4,-6.6 -2.2,-6.6 -2.2,-4.1
  body extent -4.95,-5.79 4.95,5.89, height 2.31
FP-SDEM20161T-4R7MS_SMD2-MFG [mm]
  rrect15% 0.65x1.6 smd paste+0 mask+0: 1(-0.675,0) 2(0.675,0)
  silkscreen extent -1.05,-1.22 1.05,1.2, body extent -1.15,-0.95 1.15,0.95, height 0.25
RQS0052A-MFG [mm]
  rrect10% 1.05x1.05 smd paste+0 mask+0: 1(-5.675,5.2) 16(-5.675,-5.2) 27(5.675,-5.2) 42(5.675,5.2)
  rrect25% 1.05x0.4 smd paste+0 mask+0: 2(-5.675,4.225) 3(-5.675,3.575) 4(-5.675,2.925) 5(-5.675,2.275) 6(-5.675,1.625) 7(-5.675,0.975) 8(-5.675,0.325) 9(-5.675,-0.325) 10(-5.675,-0.975) 11(-5.675,-1.625) 12(-5.675,-2.275) 13(-5.675,-2.925) 14(-5.675,-3.575) 15(-5.675,-4.225) 28(5.675,-4.225) 29(5.675,-3.575) 30(5.675,-2.925) 31(5.675,-2.275) 32(5.675,-1.625) 33(5.675,-0.975) 34(5.675,-0.325) 35(5.675,0.325) 36(5.675,0.975) 37(5.675,1.625) 38(5.675,2.275) 39(5.675,2.925) 40(5.675,3.575) 41(5.675,4.225)
  rrect25% 0.4x1.05 smd paste+0 mask+0: 17(-1.935,-5.675) 18(-1.285,-5.675) 19(-0.635,-5.675) 20(0.015,-5.675) 21(0.665,-5.675) 22(1.315,-5.675) 23(1.965,-5.675) 24(2.615,-5.675) 25(3.265,-5.675) 26(3.915,-5.675) 43(3.915,5.675) 44(3.265,5.675) 45(2.615,5.675) 46(1.965,5.675) 47(1.315,5.675) 48(0.665,5.675) 49(0.015,5.675) 50(-0.635,5.675) 51(-1.285,5.675) 52(-1.935,5.675)
  silkscreen extent -6.87,-6.05 4.77,6.05, body extent -6,-6 6,6, height 1
SMB [mil] "Molded Diode, 2-Leads, Body 5.4x3.6mm, IPC Medium Density, based on OnSemi component dimensions"
  rect 85x107.99 smd: 1(-87.01,0) 2(87.01,0)
  silkscreen extent -155,-82 125,82, body extent -106,-71 106,71, height 91
SOD-123 [mm] "On Semi recommended land pattern"
  rect 0.915x1.22 smd: 1(-1.637,0) 2(1.637,0)
  silkscreen extent -2.74,-1.17 2.03,1.17, body extent -1.93,-0.9 1.93,0.9, height 1.35
TDK_ACM2520-2P [mm] "SMD, 4-Leads, Body 2.5x2mm"
  rect 0.8x0.4 smd: 1(-1.15,0.65) 2(-1.15,-0.65) 3(1.15,-0.65) 4(1.15,0.65)
  silkscreen extent -2.1,-1.2 1.45,1.2, body extent -1.35,-1.1 1.35,1.1, height 1.3
TP_H045P075#1 [mm] "TP_H0.45P0.75"
  round 0.75 hole 3.2: 1(14.863,-0.874)
TP_H045P075#2 [mm] "TP_H0.45P0.75"
  round 0.75 hole 1: 1(1.155,-0.667)
TP_H045P075#3 [mm] "TP_H0.45P0.75"
  round 0.75 hole 1: 1(-2.038,0.842)
TP_H045P075#4 [mm] "TP_H0.45P0.75"
  round 0.75 hole 3.2: 1(3.38,-4.994)
Wurth_760390013 [mil] "Wurth"
  rect 44x38 smd: 1(-180,100) 2(-180,0) 3(-180,-100) 4(180,-100) 5(180,0) 6(180,100)
  silkscreen extent -190,-132 85,145, body extent -198,-135 198,130, height 166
